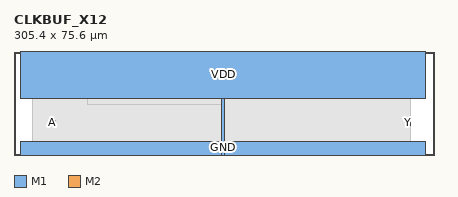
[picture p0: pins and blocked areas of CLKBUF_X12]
MACRO CLKBUF_X12
  CLASS CORE ;
  ORIGIN 0 0 ;
  SIZE 305.400 BY 75.600 ;
  SYMMETRY X Y ;
  SITE TR1um_access_site ;
  PIN VDD
    DIRECTION INOUT ;
    USE POWER ;
    PORT
      LAYER M1 ;
        RECT 151.150 0.000 152.950 41.000 ;
      LAYER M1 ;
        RECT 5.000 41.000 299.100 75.600 ;
    END
  END VDD
  PIN GND
    DIRECTION INOUT ;
    USE GROUND ;
    PORT
      LAYER M1 ;
        RECT 5.000 0.000 299.100 9.800 ;
    END
  END GND
  PIN A
    DIRECTION INPUT ;
    USE SIGNAL ;
    PORT
      LAYER M2 ;
        RECT 26.600 21.600 30.000 25.000 ;
    END
  END A
  PIN Y
    DIRECTION OUTPUT ;
    USE SIGNAL ;
    PORT
      LAYER M2 ;
        RECT 285.100 21.600 288.500 25.000 ;
    END
  END Y
  OBS
    LAYER M1 ;
      RECT 53.100 6.400 151.150 14.400 ;
    LAYER M1 ;
      RECT 59.100 16.400 151.150 19.000 ;
    LAYER M1 ;
      RECT 19.100 16.400 41.700 34.400 ;
    LAYER M1 ;
      RECT 59.100 31.800 151.150 34.400 ;
    LAYER M1 ;
      RECT 152.950 16.400 281.700 34.400 ;
    LAYER M1 ;
      RECT 13.100 6.400 151.150 51.200 ;
    LAYER M1 ;
      RECT 53.100 36.400 151.700 51.200 ;
    LAYER M1 ;
      RECT 152.950 6.400 288.500 51.200 ;
    LAYER V1 ;
      RECT 27.600 22.600 29.000 24.000 ;
    LAYER V1 ;
      RECT 286.100 22.600 287.500 24.000 ;
  END
END CLKBUF_X12
